VERSION 5.8 ;
BUSBITCHARS "[]" ;
DIVIDERCHAR "/" ;
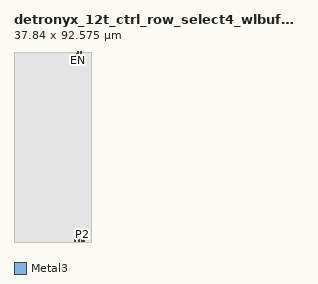
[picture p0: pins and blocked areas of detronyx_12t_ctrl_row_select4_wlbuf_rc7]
MACRO detronyx_12t_ctrl_row_select4_wlbuf_rc7
  CLASS BLOCK ;
  FOREIGN detronyx_12t_ctrl_row_select4_wlbuf_rc7 0.000 0.000 ;
  ORIGIN 0.000 0.000 ;
  SIZE 37.840000 BY 92.575000 ;
  SYMMETRY X Y ;
  PIN VDD
    DIRECTION INOUT ;
    USE POWER ;
    PORT
      LAYER Metal3 ;
        RECT 30.260000 90.875000 30.620000 92.075000 ;
    END
  END VDD
  PIN VSS
    DIRECTION INOUT ;
    USE GROUND ;
    PORT
      LAYER Metal3 ;
        RECT 29.560000 0.200000 29.920000 1.400000 ;
    END
  END VSS
  PIN P0
    DIRECTION INPUT ;
    USE SIGNAL ;
    PORT
      LAYER Metal3 ;
        RECT 31.660000 0.400000 32.020000 1.200000 ;
    END
  END P0
  PIN P1
    DIRECTION INPUT ;
    USE SIGNAL ;
    PORT
      LAYER Metal3 ;
        RECT 32.360000 91.975000 32.720000 92.775000 ;
    END
  END P1
  PIN P2
    DIRECTION INPUT ;
    USE SIGNAL ;
    PORT
      LAYER Metal3 ;
        RECT 33.060000 0.400000 33.420000 1.200000 ;
    END
  END P2
  PIN EN
    DIRECTION INPUT ;
    USE SIGNAL ;
    PORT
      LAYER Metal3 ;
        RECT 30.960000 91.975000 31.320000 92.775000 ;
    END
  END EN
  PIN WL
    DIRECTION OUTPUT ;
    USE SIGNAL ;
    PORT
      LAYER Metal3 ;
        RECT 33.760000 0.400000 34.120000 1.200000 ;
    END
  END WL
  OBS
    LAYER Metal1 ;
      RECT 0.000000 0.000000 37.840000 92.575000 ;
    LAYER Metal2 ;
      RECT 0.000000 0.000000 37.840000 92.575000 ;
  END
END detronyx_12t_ctrl_row_select4_wlbuf_rc7
END LIBRARY
